VERSION 5.7 ;
  NOWIREEXTENSIONATPIN ON ;
  DIVIDERCHAR "/" ;
  BUSBITCHARS "[]" ;
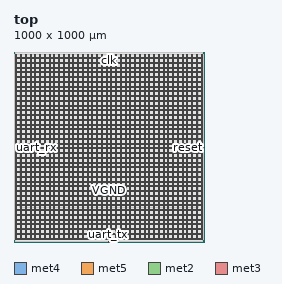
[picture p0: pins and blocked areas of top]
MACRO top
  CLASS BLOCK ;
  FOREIGN top ;
  ORIGIN 0.000 0.000 ;
  SIZE 1000.000 BY 1000.000 ;
  PIN VGND
    DIRECTION INOUT ;
    USE GROUND ;
    PORT
      LAYER met4 ;
        RECT 13.020 10.640 14.620 987.600 ;
    END
    PORT
      LAYER met4 ;
        RECT 38.020 10.640 39.620 987.600 ;
    END
    PORT
      LAYER met4 ;
        RECT 63.020 10.640 64.620 987.600 ;
    END
    PORT
      LAYER met4 ;
        RECT 88.020 10.640 89.620 987.600 ;
    END
    PORT
      LAYER met4 ;
        RECT 113.020 10.640 114.620 987.600 ;
    END
    PORT
      LAYER met4 ;
        RECT 138.020 10.640 139.620 987.600 ;
    END
    PORT
      LAYER met4 ;
        RECT 163.020 10.640 164.620 987.600 ;
    END
    PORT
      LAYER met4 ;
        RECT 188.020 10.640 189.620 987.600 ;
    END
    PORT
      LAYER met4 ;
        RECT 213.020 10.640 214.620 987.600 ;
    END
    PORT
      LAYER met4 ;
        RECT 238.020 10.640 239.620 987.600 ;
    END
    PORT
      LAYER met4 ;
        RECT 263.020 10.640 264.620 987.600 ;
    END
    PORT
      LAYER met4 ;
        RECT 288.020 10.640 289.620 987.600 ;
    END
    PORT
      LAYER met4 ;
        RECT 313.020 10.640 314.620 987.600 ;
    END
    PORT
      LAYER met4 ;
        RECT 338.020 10.640 339.620 987.600 ;
    END
    PORT
      LAYER met4 ;
        RECT 363.020 10.640 364.620 987.600 ;
    END
    PORT
      LAYER met4 ;
        RECT 388.020 10.640 389.620 987.600 ;
    END
    PORT
      LAYER met4 ;
        RECT 413.020 10.640 414.620 987.600 ;
    END
    PORT
      LAYER met4 ;
        RECT 438.020 10.640 439.620 987.600 ;
    END
    PORT
      LAYER met4 ;
        RECT 463.020 10.640 464.620 987.600 ;
    END
    PORT
      LAYER met4 ;
        RECT 488.020 10.640 489.620 987.600 ;
    END
    PORT
      LAYER met4 ;
        RECT 513.020 10.640 514.620 987.600 ;
    END
    PORT
      LAYER met4 ;
        RECT 538.020 10.640 539.620 987.600 ;
    END
    PORT
      LAYER met4 ;
        RECT 563.020 10.640 564.620 987.600 ;
    END
    PORT
      LAYER met4 ;
        RECT 588.020 10.640 589.620 987.600 ;
    END
    PORT
      LAYER met4 ;
        RECT 613.020 10.640 614.620 987.600 ;
    END
    PORT
      LAYER met4 ;
        RECT 638.020 10.640 639.620 987.600 ;
    END
    PORT
      LAYER met4 ;
        RECT 663.020 10.640 664.620 987.600 ;
    END
    PORT
      LAYER met4 ;
        RECT 688.020 10.640 689.620 987.600 ;
    END
    PORT
      LAYER met4 ;
        RECT 713.020 10.640 714.620 987.600 ;
    END
    PORT
      LAYER met4 ;
        RECT 738.020 10.640 739.620 987.600 ;
    END
    PORT
      LAYER met4 ;
        RECT 763.020 10.640 764.620 987.600 ;
    END
    PORT
      LAYER met4 ;
        RECT 788.020 10.640 789.620 987.600 ;
    END
    PORT
      LAYER met4 ;
        RECT 813.020 10.640 814.620 987.600 ;
    END
    PORT
      LAYER met4 ;
        RECT 838.020 10.640 839.620 987.600 ;
    END
    PORT
      LAYER met4 ;
        RECT 863.020 10.640 864.620 987.600 ;
    END
    PORT
      LAYER met4 ;
        RECT 888.020 10.640 889.620 987.600 ;
    END
    PORT
      LAYER met4 ;
        RECT 913.020 10.640 914.620 987.600 ;
    END
    PORT
      LAYER met4 ;
        RECT 938.020 10.640 939.620 987.600 ;
    END
    PORT
      LAYER met4 ;
        RECT 963.020 10.640 964.620 987.600 ;
    END
    PORT
      LAYER met4 ;
        RECT 988.020 10.640 989.620 987.600 ;
    END
    PORT
      LAYER met5 ;
        RECT 5.280 18.380 994.300 19.980 ;
    END
    PORT
      LAYER met5 ;
        RECT 5.280 43.380 994.300 44.980 ;
    END
    PORT
      LAYER met5 ;
        RECT 5.280 68.380 994.300 69.980 ;
    END
    PORT
      LAYER met5 ;
        RECT 5.280 93.380 994.300 94.980 ;
    END
    PORT
      LAYER met5 ;
        RECT 5.280 118.380 994.300 119.980 ;
    END
    PORT
      LAYER met5 ;
        RECT 5.280 143.380 994.300 144.980 ;
    END
    PORT
      LAYER met5 ;
        RECT 5.280 168.380 994.300 169.980 ;
    END
    PORT
      LAYER met5 ;
        RECT 5.280 193.380 994.300 194.980 ;
    END
    PORT
      LAYER met5 ;
        RECT 5.280 218.380 994.300 219.980 ;
    END
    PORT
      LAYER met5 ;
        RECT 5.280 243.380 994.300 244.980 ;
    END
    PORT
      LAYER met5 ;
        RECT 5.280 268.380 994.300 269.980 ;
    END
    PORT
      LAYER met5 ;
        RECT 5.280 293.380 994.300 294.980 ;
    END
    PORT
      LAYER met5 ;
        RECT 5.280 318.380 994.300 319.980 ;
    END
    PORT
      LAYER met5 ;
        RECT 5.280 343.380 994.300 344.980 ;
    END
    PORT
      LAYER met5 ;
        RECT 5.280 368.380 994.300 369.980 ;
    END
    PORT
      LAYER met5 ;
        RECT 5.280 393.380 994.300 394.980 ;
    END
    PORT
      LAYER met5 ;
        RECT 5.280 418.380 994.300 419.980 ;
    END
    PORT
      LAYER met5 ;
        RECT 5.280 443.380 994.300 444.980 ;
    END
    PORT
      LAYER met5 ;
        RECT 5.280 468.380 994.300 469.980 ;
    END
    PORT
      LAYER met5 ;
        RECT 5.280 493.380 994.300 494.980 ;
    END
    PORT
      LAYER met5 ;
        RECT 5.280 518.380 994.300 519.980 ;
    END
    PORT
      LAYER met5 ;
        RECT 5.280 543.380 994.300 544.980 ;
    END
    PORT
      LAYER met5 ;
        RECT 5.280 568.380 994.300 569.980 ;
    END
    PORT
      LAYER met5 ;
        RECT 5.280 593.380 994.300 594.980 ;
    END
    PORT
      LAYER met5 ;
        RECT 5.280 618.380 994.300 619.980 ;
    END
    PORT
      LAYER met5 ;
        RECT 5.280 643.380 994.300 644.980 ;
    END
    PORT
      LAYER met5 ;
        RECT 5.280 668.380 994.300 669.980 ;
    END
    PORT
      LAYER met5 ;
        RECT 5.280 693.380 994.300 694.980 ;
    END
    PORT
      LAYER met5 ;
        RECT 5.280 718.380 994.300 719.980 ;
    END
    PORT
      LAYER met5 ;
        RECT 5.280 743.380 994.300 744.980 ;
    END
    PORT
      LAYER met5 ;
        RECT 5.280 768.380 994.300 769.980 ;
    END
    PORT
      LAYER met5 ;
        RECT 5.280 793.380 994.300 794.980 ;
    END
    PORT
      LAYER met5 ;
        RECT 5.280 818.380 994.300 819.980 ;
    END
    PORT
      LAYER met5 ;
        RECT 5.280 843.380 994.300 844.980 ;
    END
    PORT
      LAYER met5 ;
        RECT 5.280 868.380 994.300 869.980 ;
    END
    PORT
      LAYER met5 ;
        RECT 5.280 893.380 994.300 894.980 ;
    END
    PORT
      LAYER met5 ;
        RECT 5.280 918.380 994.300 919.980 ;
    END
    PORT
      LAYER met5 ;
        RECT 5.280 943.380 994.300 944.980 ;
    END
    PORT
      LAYER met5 ;
        RECT 5.280 968.380 994.300 969.980 ;
    END
  END VGND
  PIN VPWR
    DIRECTION INOUT ;
    USE POWER ;
    PORT
      LAYER met4 ;
        RECT 9.720 10.640 11.320 987.600 ;
    END
    PORT
      LAYER met4 ;
        RECT 34.720 10.640 36.320 987.600 ;
    END
    PORT
      LAYER met4 ;
        RECT 59.720 10.640 61.320 987.600 ;
    END
    PORT
      LAYER met4 ;
        RECT 84.720 10.640 86.320 987.600 ;
    END
    PORT
      LAYER met4 ;
        RECT 109.720 10.640 111.320 987.600 ;
    END
    PORT
      LAYER met4 ;
        RECT 134.720 10.640 136.320 987.600 ;
    END
    PORT
      LAYER met4 ;
        RECT 159.720 10.640 161.320 987.600 ;
    END
    PORT
      LAYER met4 ;
        RECT 184.720 10.640 186.320 987.600 ;
    END
    PORT
      LAYER met4 ;
        RECT 209.720 10.640 211.320 987.600 ;
    END
    PORT
      LAYER met4 ;
        RECT 234.720 10.640 236.320 987.600 ;
    END
    PORT
      LAYER met4 ;
        RECT 259.720 10.640 261.320 987.600 ;
    END
    PORT
      LAYER met4 ;
        RECT 284.720 10.640 286.320 987.600 ;
    END
    PORT
      LAYER met4 ;
        RECT 309.720 10.640 311.320 987.600 ;
    END
    PORT
      LAYER met4 ;
        RECT 334.720 10.640 336.320 987.600 ;
    END
    PORT
      LAYER met4 ;
        RECT 359.720 10.640 361.320 987.600 ;
    END
    PORT
      LAYER met4 ;
        RECT 384.720 10.640 386.320 987.600 ;
    END
    PORT
      LAYER met4 ;
        RECT 409.720 10.640 411.320 987.600 ;
    END
    PORT
      LAYER met4 ;
        RECT 434.720 10.640 436.320 987.600 ;
    END
    PORT
      LAYER met4 ;
        RECT 459.720 10.640 461.320 987.600 ;
    END
    PORT
      LAYER met4 ;
        RECT 484.720 10.640 486.320 987.600 ;
    END
    PORT
      LAYER met4 ;
        RECT 509.720 10.640 511.320 987.600 ;
    END
    PORT
      LAYER met4 ;
        RECT 534.720 10.640 536.320 987.600 ;
    END
    PORT
      LAYER met4 ;
        RECT 559.720 10.640 561.320 987.600 ;
    END
    PORT
      LAYER met4 ;
        RECT 584.720 10.640 586.320 987.600 ;
    END
    PORT
      LAYER met4 ;
        RECT 609.720 10.640 611.320 987.600 ;
    END
    PORT
      LAYER met4 ;
        RECT 634.720 10.640 636.320 987.600 ;
    END
    PORT
      LAYER met4 ;
        RECT 659.720 10.640 661.320 987.600 ;
    END
    PORT
      LAYER met4 ;
        RECT 684.720 10.640 686.320 987.600 ;
    END
    PORT
      LAYER met4 ;
        RECT 709.720 10.640 711.320 987.600 ;
    END
    PORT
      LAYER met4 ;
        RECT 734.720 10.640 736.320 987.600 ;
    END
    PORT
      LAYER met4 ;
        RECT 759.720 10.640 761.320 987.600 ;
    END
    PORT
      LAYER met4 ;
        RECT 784.720 10.640 786.320 987.600 ;
    END
    PORT
      LAYER met4 ;
        RECT 809.720 10.640 811.320 987.600 ;
    END
    PORT
      LAYER met4 ;
        RECT 834.720 10.640 836.320 987.600 ;
    END
    PORT
      LAYER met4 ;
        RECT 859.720 10.640 861.320 987.600 ;
    END
    PORT
      LAYER met4 ;
        RECT 884.720 10.640 886.320 987.600 ;
    END
    PORT
      LAYER met4 ;
        RECT 909.720 10.640 911.320 987.600 ;
    END
    PORT
      LAYER met4 ;
        RECT 934.720 10.640 936.320 987.600 ;
    END
    PORT
      LAYER met4 ;
        RECT 959.720 10.640 961.320 987.600 ;
    END
    PORT
      LAYER met4 ;
        RECT 984.720 10.640 986.320 987.600 ;
    END
    PORT
      LAYER met5 ;
        RECT 5.280 15.080 994.300 16.680 ;
    END
    PORT
      LAYER met5 ;
        RECT 5.280 40.080 994.300 41.680 ;
    END
    PORT
      LAYER met5 ;
        RECT 5.280 65.080 994.300 66.680 ;
    END
    PORT
      LAYER met5 ;
        RECT 5.280 90.080 994.300 91.680 ;
    END
    PORT
      LAYER met5 ;
        RECT 5.280 115.080 994.300 116.680 ;
    END
    PORT
      LAYER met5 ;
        RECT 5.280 140.080 994.300 141.680 ;
    END
    PORT
      LAYER met5 ;
        RECT 5.280 165.080 994.300 166.680 ;
    END
    PORT
      LAYER met5 ;
        RECT 5.280 190.080 994.300 191.680 ;
    END
    PORT
      LAYER met5 ;
        RECT 5.280 215.080 994.300 216.680 ;
    END
    PORT
      LAYER met5 ;
        RECT 5.280 240.080 994.300 241.680 ;
    END
    PORT
      LAYER met5 ;
        RECT 5.280 265.080 994.300 266.680 ;
    END
    PORT
      LAYER met5 ;
        RECT 5.280 290.080 994.300 291.680 ;
    END
    PORT
      LAYER met5 ;
        RECT 5.280 315.080 994.300 316.680 ;
    END
    PORT
      LAYER met5 ;
        RECT 5.280 340.080 994.300 341.680 ;
    END
    PORT
      LAYER met5 ;
        RECT 5.280 365.080 994.300 366.680 ;
    END
    PORT
      LAYER met5 ;
        RECT 5.280 390.080 994.300 391.680 ;
    END
    PORT
      LAYER met5 ;
        RECT 5.280 415.080 994.300 416.680 ;
    END
    PORT
      LAYER met5 ;
        RECT 5.280 440.080 994.300 441.680 ;
    END
    PORT
      LAYER met5 ;
        RECT 5.280 465.080 994.300 466.680 ;
    END
    PORT
      LAYER met5 ;
        RECT 5.280 490.080 994.300 491.680 ;
    END
    PORT
      LAYER met5 ;
        RECT 5.280 515.080 994.300 516.680 ;
    END
    PORT
      LAYER met5 ;
        RECT 5.280 540.080 994.300 541.680 ;
    END
    PORT
      LAYER met5 ;
        RECT 5.280 565.080 994.300 566.680 ;
    END
    PORT
      LAYER met5 ;
        RECT 5.280 590.080 994.300 591.680 ;
    END
    PORT
      LAYER met5 ;
        RECT 5.280 615.080 994.300 616.680 ;
    END
    PORT
      LAYER met5 ;
        RECT 5.280 640.080 994.300 641.680 ;
    END
    PORT
      LAYER met5 ;
        RECT 5.280 665.080 994.300 666.680 ;
    END
    PORT
      LAYER met5 ;
        RECT 5.280 690.080 994.300 691.680 ;
    END
    PORT
      LAYER met5 ;
        RECT 5.280 715.080 994.300 716.680 ;
    END
    PORT
      LAYER met5 ;
        RECT 5.280 740.080 994.300 741.680 ;
    END
    PORT
      LAYER met5 ;
        RECT 5.280 765.080 994.300 766.680 ;
    END
    PORT
      LAYER met5 ;
        RECT 5.280 790.080 994.300 791.680 ;
    END
    PORT
      LAYER met5 ;
        RECT 5.280 815.080 994.300 816.680 ;
    END
    PORT
      LAYER met5 ;
        RECT 5.280 840.080 994.300 841.680 ;
    END
    PORT
      LAYER met5 ;
        RECT 5.280 865.080 994.300 866.680 ;
    END
    PORT
      LAYER met5 ;
        RECT 5.280 890.080 994.300 891.680 ;
    END
    PORT
      LAYER met5 ;
        RECT 5.280 915.080 994.300 916.680 ;
    END
    PORT
      LAYER met5 ;
        RECT 5.280 940.080 994.300 941.680 ;
    END
    PORT
      LAYER met5 ;
        RECT 5.280 965.080 994.300 966.680 ;
    END
  END VPWR
  PIN clk
    DIRECTION INPUT ;
    USE SIGNAL ;
    ANTENNAGATEAREA 1.721400 ;
    ANTENNADIFFAREA 0.869400 ;
    PORT
      LAYER met2 ;
        RECT 499.650 996.000 499.930 1000.000 ;
    END
  END clk
  PIN reset
    DIRECTION INPUT ;
    USE SIGNAL ;
    ANTENNAGATEAREA 0.631200 ;
    ANTENNADIFFAREA 0.434700 ;
    PORT
      LAYER met3 ;
        RECT 996.000 499.160 1000.000 499.760 ;
    END
  END reset
  PIN uart_rx
    DIRECTION INPUT ;
    USE SIGNAL ;
    ANTENNAGATEAREA 0.560700 ;
    ANTENNADIFFAREA 0.434700 ;
    PORT
      LAYER met3 ;
        RECT 0.000 499.160 4.000 499.760 ;
    END
  END uart_rx
  PIN uart_tx
    DIRECTION OUTPUT TRISTATE ;
    USE SIGNAL ;
    ANTENNADIFFAREA 0.383400 ;
    PORT
      LAYER met2 ;
        RECT 499.650 0.000 499.930 4.000 ;
    END
  END uart_tx
  OBS
      LAYER li1 ;
        RECT 5.520 10.795 994.060 987.445 ;
      LAYER met1 ;
        RECT 5.520 10.640 994.360 987.600 ;
      LAYER met2 ;
        RECT 7.000 995.720 499.370 996.000 ;
        RECT 500.210 995.720 992.590 996.000 ;
        RECT 7.000 4.280 992.590 995.720 ;
        RECT 7.000 4.000 499.370 4.280 ;
        RECT 500.210 4.000 992.590 4.280 ;
      LAYER met3 ;
        RECT 4.000 500.160 996.000 987.525 ;
        RECT 4.400 498.760 995.600 500.160 ;
        RECT 4.000 10.715 996.000 498.760 ;
      LAYER met4 ;
        RECT 30.655 179.015 34.320 793.385 ;
        RECT 36.720 179.015 37.620 793.385 ;
        RECT 40.020 179.015 59.320 793.385 ;
        RECT 61.720 179.015 62.620 793.385 ;
        RECT 65.020 179.015 84.320 793.385 ;
        RECT 86.720 179.015 87.620 793.385 ;
        RECT 90.020 179.015 109.320 793.385 ;
        RECT 111.720 179.015 112.620 793.385 ;
        RECT 115.020 179.015 134.320 793.385 ;
        RECT 136.720 179.015 137.620 793.385 ;
        RECT 140.020 179.015 159.320 793.385 ;
        RECT 161.720 179.015 162.620 793.385 ;
        RECT 165.020 179.015 184.320 793.385 ;
        RECT 186.720 179.015 187.620 793.385 ;
        RECT 190.020 179.015 209.320 793.385 ;
        RECT 211.720 179.015 212.620 793.385 ;
        RECT 215.020 179.015 234.320 793.385 ;
        RECT 236.720 179.015 237.620 793.385 ;
        RECT 240.020 179.015 259.320 793.385 ;
        RECT 261.720 179.015 262.620 793.385 ;
        RECT 265.020 179.015 284.320 793.385 ;
        RECT 286.720 179.015 287.620 793.385 ;
        RECT 290.020 179.015 309.320 793.385 ;
        RECT 311.720 179.015 312.620 793.385 ;
        RECT 315.020 179.015 334.320 793.385 ;
        RECT 336.720 179.015 337.620 793.385 ;
        RECT 340.020 179.015 359.320 793.385 ;
        RECT 361.720 179.015 362.620 793.385 ;
        RECT 365.020 179.015 384.320 793.385 ;
        RECT 386.720 179.015 387.620 793.385 ;
        RECT 390.020 179.015 409.320 793.385 ;
        RECT 411.720 179.015 412.620 793.385 ;
        RECT 415.020 179.015 434.320 793.385 ;
        RECT 436.720 179.015 437.620 793.385 ;
        RECT 440.020 179.015 459.320 793.385 ;
        RECT 461.720 179.015 462.620 793.385 ;
        RECT 465.020 179.015 484.320 793.385 ;
        RECT 486.720 179.015 487.620 793.385 ;
        RECT 490.020 179.015 509.320 793.385 ;
        RECT 511.720 179.015 512.620 793.385 ;
        RECT 515.020 179.015 534.320 793.385 ;
        RECT 536.720 179.015 537.620 793.385 ;
        RECT 540.020 179.015 559.320 793.385 ;
        RECT 561.720 179.015 562.620 793.385 ;
        RECT 565.020 179.015 584.320 793.385 ;
        RECT 586.720 179.015 587.620 793.385 ;
        RECT 590.020 179.015 609.320 793.385 ;
        RECT 611.720 179.015 612.620 793.385 ;
        RECT 615.020 179.015 634.320 793.385 ;
        RECT 636.720 179.015 637.620 793.385 ;
        RECT 640.020 179.015 659.320 793.385 ;
        RECT 661.720 179.015 662.620 793.385 ;
        RECT 665.020 179.015 684.320 793.385 ;
        RECT 686.720 179.015 687.620 793.385 ;
        RECT 690.020 179.015 709.320 793.385 ;
        RECT 711.720 179.015 712.620 793.385 ;
        RECT 715.020 179.015 734.320 793.385 ;
        RECT 736.720 179.015 737.620 793.385 ;
        RECT 740.020 179.015 759.320 793.385 ;
        RECT 761.720 179.015 762.620 793.385 ;
        RECT 765.020 179.015 784.320 793.385 ;
        RECT 786.720 179.015 787.620 793.385 ;
        RECT 790.020 179.015 809.320 793.385 ;
        RECT 811.720 179.015 812.620 793.385 ;
        RECT 815.020 179.015 834.320 793.385 ;
        RECT 836.720 179.015 837.620 793.385 ;
        RECT 840.020 179.015 859.320 793.385 ;
        RECT 861.720 179.015 862.620 793.385 ;
        RECT 865.020 179.015 884.320 793.385 ;
        RECT 886.720 179.015 887.620 793.385 ;
        RECT 890.020 179.015 909.320 793.385 ;
        RECT 911.720 179.015 912.620 793.385 ;
        RECT 915.020 179.015 934.320 793.385 ;
        RECT 936.720 179.015 937.620 793.385 ;
        RECT 940.020 179.015 959.320 793.385 ;
        RECT 961.720 179.015 962.620 793.385 ;
        RECT 965.020 179.015 973.065 793.385 ;
  END
END top
END LIBRARY

